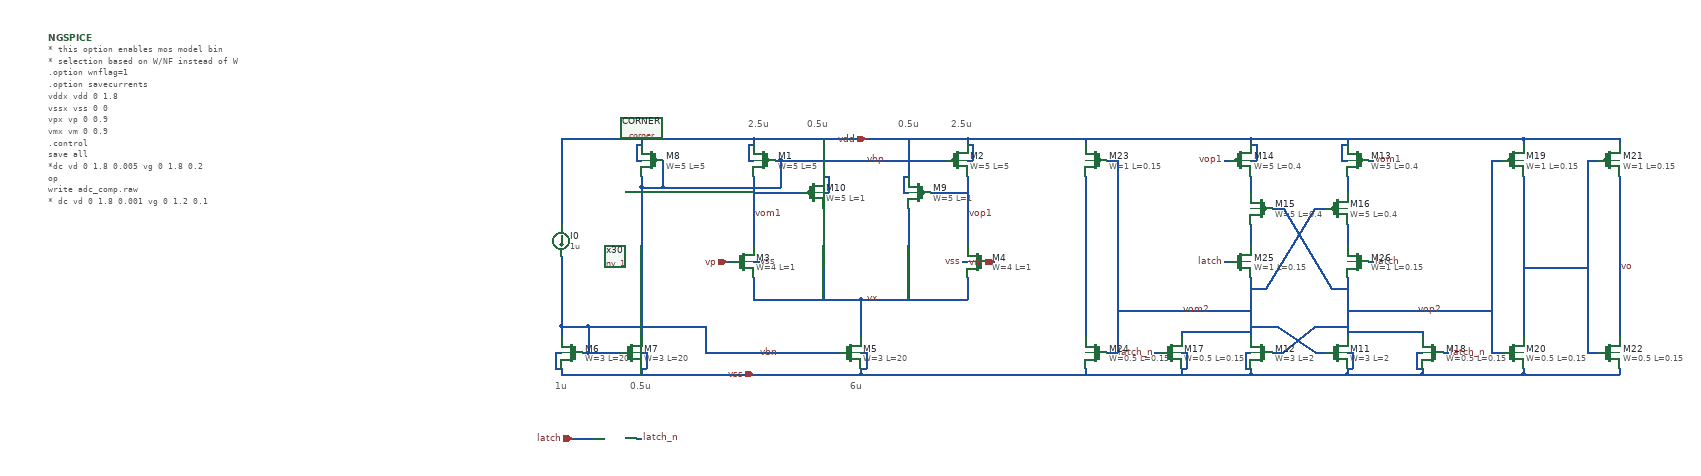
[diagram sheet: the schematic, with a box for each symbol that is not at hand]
v {xschem version=3.4.5 file_version=1.2
}
G {}
K {}
V {}
S {}
E {}
T {1u} -230 200 0 0 0.4 0.4 {}
T {0.5u} -90 200 0 0 0.4 0.4 {}
T {6u} 320 200 0 0 0.4 0.4 {}
T {2.5u} 130 -290 0 0 0.4 0.4 {}
T {2.5u} 510 -290 0 0 0.4 0.4 {}
T {0.5u} 240 -290 0 0 0.4 0.4 {}
T {0.5u} 410 -290 0 0 0.4 0.4 {}
T {0.5u} -100 -290 0 0 0.4 0.4 {}
N 140 -180 140 -50 {
lab=vom1}
N 540 -180 540 -50 {
lab=vop1}
N 130 -210 140 -210 {
lab=vdd}
N 540 -210 550 -210 {
lab=vdd}
N 330 -210 380 -210 {
lab=vbp}
N 140 10 140 50 {
lab=vx}
N 180 -210 190 -210 {
lab=vbp}
N 200 50 340 50 {
lab=vx}
N 340 50 340 110 {
lab=vx}
N -230 150 -220 150 {
lab=vss}
N -220 180 -220 190 {
lab=vss}
N -220 110 -220 120 {
lab=vbn}
N -180 150 -170 150 {
lab=vbn}
N -170 100 -170 150 {
lab=vbn}
N -220 100 -170 100 {
lab=vbn}
N -220 100 -220 110 {
lab=vbn}
N -230 150 -230 180 {
lab=vss}
N -230 180 -220 180 {
lab=vss}
N 340 150 350 150 {
lab=vss}
N 340 180 340 190 {
lab=vss}
N 340 110 340 120 {
lab=vx}
N 290 150 300 150 {
lab=vbn}
N 350 150 350 180 {
lab=vss}
N 340 180 350 180 {
lab=vss}
N -220 -30 -220 100 {
lab=vbn}
N 130 -240 130 -210 {
lab=vdd}
N 130 -240 140 -240 {
lab=vdd}
N 550 -240 550 -210 {
lab=vdd}
N 540 -240 550 -240 {
lab=vdd}
N 140 -250 140 -240 {
lab=vdd}
N 200 -250 340 -250 {
lab=vdd}
N 540 -250 540 -240 {
lab=vdd}
N 50 150 210 150 {
lab=vbn}
N 490 50 540 50 {
lab=vx}
N 540 10 540 50 {
lab=vx}
N 140 50 200 50 {
lab=vx}
N 190 -210 250 -210 {
lab=vbp}
N 450 -210 500 -210 {
lab=vbp}
N 490 -250 540 -250 {
lab=vdd}
N 140 -250 200 -250 {
lab=vdd}
N 90 -20 100 -20 {
lab=vp}
N 580 -20 590 -20 {
lab=vm}
N 530 -20 540 -20 {
lab=vss}
N 140 -20 150 -20 {
lab=vss}
N 190 -210 190 -160 {
lab=vbp}
N -220 -250 -220 -90 {
lab=vdd}
N 0 -250 140 -250 {
lab=vdd}
N -170 150 -110 150 {
lab=vbn}
N -220 190 30 190 {
lab=vss}
N -70 180 -70 190 {
lab=vss}
N -70 150 -60 150 {
lab=vss}
N -60 150 -60 170 {
lab=vss}
N -60 170 -60 180 {
lab=vss}
N -70 180 -60 180 {
lab=vss}
N -170 100 50 100 {
lab=vbn}
N 50 100 50 150 {
lab=vbn}
N 30 190 260 190 {
lab=vss}
N -220 -250 0 -250 {
lab=vdd}
N -70 -160 -70 120 {
lab=vbp}
N -70 -180 -70 -160 {
lab=vbp}
N -70 -160 -30 -160 {
lab=vbp}
N -70 -250 -70 -240 {
lab=vdd}
N -80 -210 -70 -210 {
lab=vdd}
N -80 -240 -80 -210 {
lab=vdd}
N -80 -240 -70 -240 {
lab=vdd}
N -30 -210 -30 -160 {
lab=vbp}
N 340 -250 420 -250 {
lab=vdd}
N 250 -210 330 -210 {
lab=vbp}
N 340 50 420 50 {
lab=vx}
N 420 -250 490 -250 {
lab=vdd}
N 380 -210 450 -210 {
lab=vbp}
N 420 50 490 50 {
lab=vx}
N 210 150 290 150 {
lab=vbn}
N 260 190 340 190 {
lab=vss}
N 140 -150 230 -150 {
lab=vom1}
N 470 -150 540 -150 {
lab=vop1}
N 270 -250 270 -180 {
lab=vdd}
N 430 -250 430 -180 {
lab=vdd}
N -30 -160 190 -160 {
lab=vbp}
N 270 -150 280 -150 {
lab=vdd}
N 280 -180 280 -150 {
lab=vdd}
N 270 -180 280 -180 {
lab=vdd}
N 420 -150 430 -150 {
lab=vdd}
N 420 -180 420 -150 {
lab=vdd}
N 420 -180 430 -180 {
lab=vdd}
N 270 -120 270 50 {
lab=vx}
N 430 -120 430 50 {
lab=vx}
N 1190 150 1210 150 {
lab=vom2}
N 1120 100 1190 150 {
lab=vom2}
N 1070 100 1120 100 {
lab=vom2}
N 1110 150 1130 150 {
lab=vop2}
N 1130 150 1190 100 {
lab=vop2}
N 1190 100 1250 100 {
lab=vop2}
N 1070 180 1070 190 {
lab=vss}
N 1070 190 1250 190 {
lab=vss}
N 1250 180 1250 190 {
lab=vss}
N 340 190 1070 190 {
lab=vss}
N 540 -250 1070 -250 {
lab=vdd}
N 1070 -250 1230 -250 {
lab=vdd}
N 1290 -210 1300 -210 {
lab=vom1}
N 1020 -210 1030 -210 {
lab=vop1}
N 1070 -250 1070 -240 {
lab=vdd}
N 1250 -250 1250 -240 {
lab=vdd}
N 1070 -210 1080 -210 {
lab=vdd}
N 1070 -240 1080 -240 {
lab=vdd}
N 1240 -210 1250 -210 {
lab=vdd}
N 1240 -240 1250 -240 {
lab=vdd}
N 940 110 940 120 {
lab=vom2}
N 940 110 1070 110 {
lab=vom2}
N 1390 110 1390 120 {
lab=vop2}
N 1250 110 1390 110 {
lab=vop2}
N 940 180 940 190 {
lab=vss}
N 1390 180 1390 190 {
lab=vss}
N 1250 190 1390 190 {
lab=vss}
N 1380 150 1390 150 {
lab=vss}
N 1380 150 1380 180 {
lab=vss}
N 1380 180 1390 180 {
lab=vss}
N 1250 150 1260 150 {
lab=vss}
N 1260 150 1260 180 {
lab=vss}
N 1250 180 1260 180 {
lab=vss}
N 1060 150 1070 150 {
lab=vss}
N 1060 150 1060 180 {
lab=vss}
N 1060 180 1070 180 {
lab=vss}
N 940 150 950 150 {
lab=vss}
N 950 150 950 180 {
lab=vss}
N 940 180 950 180 {
lab=vss}
N 890 150 900 150 {
lab=latch_n}
N 1430 150 1440 150 {
lab=latch_n}
N 1580 -250 1580 -240 {
lab=vdd}
N 1230 -250 1580 -250 {
lab=vdd}
N 1580 -180 1580 120 {
lab=#net1}
N 1580 180 1580 190 {
lab=vss}
N 1390 190 1580 190 {
lab=vss}
N 1520 150 1540 150 {
lab=vop2}
N 1520 -210 1520 150 {
lab=vop2}
N 1520 -210 1540 -210 {
lab=vop2}
N 1250 70 1520 70 {
lab=vop2}
N 1760 -180 1760 120 {
lab=vo}
N 1760 180 1760 190 {
lab=vss}
N 1700 150 1720 150 {
lab=#net1}
N 1700 -210 1700 150 {
lab=#net1}
N 1700 -210 1720 -210 {
lab=#net1}
N 1580 -10 1700 -10 {
lab=#net1}
N 1760 -250 1760 -240 {
lab=vdd}
N 1580 -250 1760 -250 {
lab=vdd}
N 1580 190 1760 190 {
lab=vss}
N 760 -250 760 -240 {
lab=vdd}
N 760 -180 760 120 {
lab=#net2}
N 760 180 760 190 {
lab=vss}
N 800 150 820 150 {
lab=vom2}
N 820 -210 820 150 {
lab=vom2}
N 800 -210 820 -210 {
lab=vom2}
N 820 70 1070 70 {
lab=vom2}
N 1080 -240 1080 -210 {
lab=vdd}
N 1240 -240 1240 -210 {
lab=vdd}
N 1070 -180 1070 -150 {
lab=#net3}
N 1250 -180 1250 -150 {
lab=#net4}
N 1070 -90 1070 -50 {
lab=#net5}
N 1250 -90 1250 -50 {
lab=#net6}
N 1070 10 1070 120 {
lab=vom2}
N 1250 10 1250 120 {
lab=vop2}
N 1110 -120 1130 -120 {
lab=vop2}
N 1130 -120 1220 30 {
lab=vop2}
N 1220 30 1250 30 {
lab=vop2}
N 1190 -120 1210 -120 {
lab=vom2}
N 1100 30 1190 -120 {
lab=vom2}
N 1070 30 1100 30 {
lab=vom2}
N 1290 -20 1300 -20 {
lab=latch}
N 1020 -20 1030 -20 {
lab=latch}
N -200 310 -160 310 {
lab=latch}
N -80 310 -70 310 {
lab=#net7}
C {sky130_fd_pr/nfet_01v8.sym} 120 -20 0 0 {name=M3
L=1
W=4
nf=4 
mult=4
ad="'int((nf+1)/2) * W/nf * 0.29'" 
pd="'2*int((nf+1)/2) * (W/nf + 0.29)'"
as="'int((nf+2)/2) * W/nf * 0.29'" 
ps="'2*int((nf+2)/2) * (W/nf + 0.29)'"
nrd="'0.29 / W'" nrs="'0.29 / W'"
sa=0 sb=0 sd=0
model=nfet_01v8_lvt
spiceprefix=X
}
C {sky130_fd_pr/nfet_01v8.sym} 560 -20 0 1 {name=M4
L=1
W=4
nf=4 
mult=4
ad="'int((nf+1)/2) * W/nf * 0.29'" 
pd="'2*int((nf+1)/2) * (W/nf + 0.29)'"
as="'int((nf+2)/2) * W/nf * 0.29'" 
ps="'2*int((nf+2)/2) * (W/nf + 0.29)'"
nrd="'0.29 / W'" nrs="'0.29 / W'"
sa=0 sb=0 sd=0
model=nfet_01v8_lvt
spiceprefix=X
}
C {sky130_fd_pr/pfet_01v8.sym} 520 -210 0 0 {name=M2
L=5
W=5
nf=1
mult=5
ad="'int((nf+1)/2) * W/nf * 0.29'" 
pd="'2*int((nf+1)/2) * (W/nf + 0.29)'"
as="'int((nf+2)/2) * W/nf * 0.29'" 
ps="'2*int((nf+2)/2) * (W/nf + 0.29)'"
nrd="'0.29 / W'" nrs="'0.29 / W'"
sa=0 sb=0 sd=0
model=pfet_01v8_lvt
spiceprefix=X
}
C {sky130_fd_pr/pfet_01v8.sym} 160 -210 0 1 {name=M1
L=5
W=5
nf=1
mult=5
ad="'int((nf+1)/2) * W/nf * 0.29'" 
pd="'2*int((nf+1)/2) * (W/nf + 0.29)'"
as="'int((nf+2)/2) * W/nf * 0.29'" 
ps="'2*int((nf+2)/2) * (W/nf + 0.29)'"
nrd="'0.29 / W'" nrs="'0.29 / W'"
sa=0 sb=0 sd=0
model=pfet_01v8_lvt
spiceprefix=X
}
C {sky130_fd_pr/nfet_01v8.sym} -200 150 0 1 {name=M6
L=20
W=3
nf=1
mult=2
ad="'int((nf+1)/2) * W/nf * 0.29'" 
pd="'2*int((nf+1)/2) * (W/nf + 0.29)'"
as="'int((nf+2)/2) * W/nf * 0.29'" 
ps="'2*int((nf+2)/2) * (W/nf + 0.29)'"
nrd="'0.29 / W'" nrs="'0.29 / W'"
sa=0 sb=0 sd=0
model=nfet_01v8
spiceprefix=X
}
C {sky130_fd_pr/nfet_01v8.sym} 320 150 0 0 {name=M5
L=20
W=3
nf=1
mult=12
ad="'int((nf+1)/2) * W/nf * 0.29'" 
pd="'2*int((nf+1)/2) * (W/nf + 0.29)'"
as="'int((nf+2)/2) * W/nf * 0.29'" 
ps="'2*int((nf+2)/2) * (W/nf + 0.29)'"
nrd="'0.29 / W'" nrs="'0.29 / W'"
sa=0 sb=0 sd=0
model=nfet_01v8
spiceprefix=X
}
C {iopin.sym} 140 190 1 0 {name=p1 lab=vss}
C {iopin.sym} 350 -250 3 0 {name=p2 lab=vdd}
C {devices/code_shown.sym} -1180 -440 0 0 {name=NGSPICE
only_toplevel=true
value="* this option enables mos model bin 
* selection based on W/NF instead of W
.option wnflag=1 
.option savecurrents
vddx vdd 0 1.8
vssx vss 0 0
vpx vp 0 0.9
vmx vm 0 0.9
.control
save all

*dc vd 0 1.8 0.005 vg 0 1.8 0.2
op
write adc_comp.raw
* dc vd 0 1.8 0.001 vg 0 1.2 0.1
print vbn vbp vx vdd vss vop1 vom1
print @m.xm5.msky130_fd_pr__nfet_01v8[gm]/@m.xm5.msky130_fd_pr__nfet_01v8[id]
print @m.xm5.msky130_fd_pr__nfet_01v8[gm]
print @m.xm5.msky130_fd_pr__nfet_01v8[vgs]-@m.xm5.msky130_fd_pr__nfet_01v8[vth]
print @m.xm5.msky130_fd_pr__nfet_01v8[id]
print @m.xm5.msky130_fd_pr__nfet_01v8[vth]
print @m.xm11.msky130_fd_pr__nfet_01v8[id]
print @m.xm1.msky130_fd_pr__pfet_01v8_lvt[vgs]-@m.xm1.msky130_fd_pr__pfet_01v8_lvt[vth]
print @m.xm1.msky130_fd_pr__pfet_01v8_lvt[vgs]
print @m.xm1.msky130_fd_pr__pfet_01v8_lvt[gm]/@m.xm1.msky130_fd_pr__pfet_01v8_lvt[id]
print @m.xm1.msky130_fd_pr__pfet_01v8_lvt[vth]
print @m.xm1.msky130_fd_pr__pfet_01v8_lvt[id]
print @m.xm3.msky130_fd_pr__nfet_01v8_lvt[vgs]-@m.xm3.msky130_fd_pr__nfet_01v8_lvt[vth]
print @m.xm3.msky130_fd_pr__nfet_01v8_lvt[vgs]
print @m.xm3.msky130_fd_pr__nfet_01v8_lvt[gm]/@m.xm3.msky130_fd_pr__nfet_01v8_lvt[id]
print @m.xm3.msky130_fd_pr__nfet_01v8_lvt[vth]
print @m.xm3.msky130_fd_pr__nfet_01v8_lvt[id]
print @m.xm10.msky130_fd_pr__pfet_01v8_lvt[id]
set appendwrite
op
.endc
"}
C {ipin.sym} 90 -20 0 0 {name=p3 lab=vp}
C {ipin.sym} 590 -20 2 0 {name=p4 lab=vm}
C {lab_wire.sym} 150 -20 2 0 {name=p5 sig_type=std_logic lab=vss}
C {lab_wire.sym} 530 -20 0 0 {name=p6 sig_type=std_logic lab=vss}
C {sky130_fd_pr/corner.sym} -540 -420 0 0 {name=CORNER only_toplevel=true corner=tt}
C {isource.sym} -220 -60 0 0 {name=I0 value=1u}
C {lab_wire.sym} 150 150 2 0 {name=p7 sig_type=std_logic lab=vbn}
C {lab_wire.sym} 350 -210 2 0 {name=p8 sig_type=std_logic lab=vbp}
C {lab_wire.sym} 350 50 2 0 {name=p9 sig_type=std_logic lab=vx}
C {sky130_fd_pr/nfet_01v8.sym} -90 150 0 0 {name=M7
L=20
W=3
nf=1
mult=1
ad="'int((nf+1)/2) * W/nf * 0.29'" 
pd="'2*int((nf+1)/2) * (W/nf + 0.29)'"
as="'int((nf+2)/2) * W/nf * 0.29'" 
ps="'2*int((nf+2)/2) * (W/nf + 0.29)'"
nrd="'0.29 / W'" nrs="'0.29 / W'"
sa=0 sb=0 sd=0
model=nfet_01v8
spiceprefix=X
}
C {sky130_fd_pr/pfet_01v8.sym} -50 -210 0 1 {name=M8
L=5
W=5
nf=1
mult=1
ad="'int((nf+1)/2) * W/nf * 0.29'" 
pd="'2*int((nf+1)/2) * (W/nf + 0.29)'"
as="'int((nf+2)/2) * W/nf * 0.29'" 
ps="'2*int((nf+2)/2) * (W/nf + 0.29)'"
nrd="'0.29 / W'" nrs="'0.29 / W'"
sa=0 sb=0 sd=0
model=pfet_01v8_lvt
spiceprefix=X
}
C {lab_wire.sym} 140 -110 2 0 {name=p10 sig_type=std_logic lab=vom1}
C {lab_wire.sym} 540 -110 2 0 {name=p11 sig_type=std_logic lab=vop1
}
C {sky130_fd_pr/pfet_01v8.sym} 450 -150 0 1 {name=M9
L=1
W=5
nf=1
mult=2
ad="'int((nf+1)/2) * W/nf * 0.29'" 
pd="'2*int((nf+1)/2) * (W/nf + 0.29)'"
as="'int((nf+2)/2) * W/nf * 0.29'" 
ps="'2*int((nf+2)/2) * (W/nf + 0.29)'"
nrd="'0.29 / W'" nrs="'0.29 / W'"
sa=0 sb=0 sd=0
model=pfet_01v8_lvt
spiceprefix=X
}
C {sky130_fd_pr/pfet_01v8.sym} 250 -150 0 0 {name=M10
L=1
W=5
nf=1
mult=2
ad="'int((nf+1)/2) * W/nf * 0.29'" 
pd="'2*int((nf+1)/2) * (W/nf + 0.29)'"
as="'int((nf+2)/2) * W/nf * 0.29'" 
ps="'2*int((nf+2)/2) * (W/nf + 0.29)'"
nrd="'0.29 / W'" nrs="'0.29 / W'"
sa=0 sb=0 sd=0
model=pfet_01v8_lvt
spiceprefix=X
}
C {sky130_fd_pr/nfet_01v8.sym} 1230 150 0 0 {name=M11
L=2
W=3
nf=1
mult=1
ad="'int((nf+1)/2) * W/nf * 0.29'" 
pd="'2*int((nf+1)/2) * (W/nf + 0.29)'"
as="'int((nf+2)/2) * W/nf * 0.29'" 
ps="'2*int((nf+2)/2) * (W/nf + 0.29)'"
nrd="'0.29 / W'" nrs="'0.29 / W'"
sa=0 sb=0 sd=0
model=nfet_01v8
spiceprefix=X
}
C {sky130_fd_pr/nfet_01v8.sym} 1090 150 0 1 {name=M12
L=2
W=3
nf=1
mult=1
ad="'int((nf+1)/2) * W/nf * 0.29'" 
pd="'2*int((nf+1)/2) * (W/nf + 0.29)'"
as="'int((nf+2)/2) * W/nf * 0.29'" 
ps="'2*int((nf+2)/2) * (W/nf + 0.29)'"
nrd="'0.29 / W'" nrs="'0.29 / W'"
sa=0 sb=0 sd=0
model=nfet_01v8
spiceprefix=X
}
C {sky130_fd_pr/pfet_01v8.sym} 1270 -210 0 1 {name=M13
L=0.4
W=5
nf=1
mult=1
ad="'int((nf+1)/2) * W/nf * 0.29'" 
pd="'2*int((nf+1)/2) * (W/nf + 0.29)'"
as="'int((nf+2)/2) * W/nf * 0.29'" 
ps="'2*int((nf+2)/2) * (W/nf + 0.29)'"
nrd="'0.29 / W'" nrs="'0.29 / W'"
sa=0 sb=0 sd=0
model=pfet_01v8_lvt
spiceprefix=X
}
C {sky130_fd_pr/pfet_01v8.sym} 1050 -210 0 0 {name=M14
L=0.4
W=5
nf=1
mult=1
ad="'int((nf+1)/2) * W/nf * 0.29'" 
pd="'2*int((nf+1)/2) * (W/nf + 0.29)'"
as="'int((nf+2)/2) * W/nf * 0.29'" 
ps="'2*int((nf+2)/2) * (W/nf + 0.29)'"
nrd="'0.29 / W'" nrs="'0.29 / W'"
sa=0 sb=0 sd=0
model=pfet_01v8_lvt
spiceprefix=X
}
C {lab_wire.sym} 1020 -210 0 0 {name=p12 sig_type=std_logic lab=vop1
}
C {lab_wire.sym} 1300 -210 0 1 {name=p13 sig_type=std_logic lab=vom1
}
C {sky130_fd_pr/nfet_01v8.sym} 920 150 0 0 {name=M17
L=0.15
W=0.5
nf=1
mult=1
ad="'int((nf+1)/2) * W/nf * 0.29'" 
pd="'2*int((nf+1)/2) * (W/nf + 0.29)'"
as="'int((nf+2)/2) * W/nf * 0.29'" 
ps="'2*int((nf+2)/2) * (W/nf + 0.29)'"
nrd="'0.29 / W'" nrs="'0.29 / W'"
sa=0 sb=0 sd=0
model=nfet_01v8
spiceprefix=X
}
C {sky130_fd_pr/nfet_01v8.sym} 1410 150 0 1 {name=M18
L=0.15
W=0.5
nf=1
mult=1
ad="'int((nf+1)/2) * W/nf * 0.29'" 
pd="'2*int((nf+1)/2) * (W/nf + 0.29)'"
as="'int((nf+2)/2) * W/nf * 0.29'" 
ps="'2*int((nf+2)/2) * (W/nf + 0.29)'"
nrd="'0.29 / W'" nrs="'0.29 / W'"
sa=0 sb=0 sd=0
model=nfet_01v8
spiceprefix=X
}
C {lab_wire.sym} 890 150 0 0 {name=p16 sig_type=std_logic lab=latch_n

}
C {lab_wire.sym} 1440 150 2 0 {name=p17 sig_type=std_logic lab=latch_n

}
C {sky130_fd_pr/pfet_01v8.sym} 1560 -210 0 0 {name=M19
L=0.15
W=1
nf=1
mult=1
ad="'int((nf+1)/2) * W/nf * 0.29'" 
pd="'2*int((nf+1)/2) * (W/nf + 0.29)'"
as="'int((nf+2)/2) * W/nf * 0.29'" 
ps="'2*int((nf+2)/2) * (W/nf + 0.29)'"
nrd="'0.29 / W'" nrs="'0.29 / W'"
sa=0 sb=0 sd=0
model=pfet_01v8
spiceprefix=X
}
C {sky130_fd_pr/nfet_01v8.sym} 1560 150 0 0 {name=M20
L=0.15
W=0.5
nf=1
mult=1
ad="'int((nf+1)/2) * W/nf * 0.29'" 
pd="'2*int((nf+1)/2) * (W/nf + 0.29)'"
as="'int((nf+2)/2) * W/nf * 0.29'" 
ps="'2*int((nf+2)/2) * (W/nf + 0.29)'"
nrd="'0.29 / W'" nrs="'0.29 / W'"
sa=0 sb=0 sd=0
model=nfet_01v8
spiceprefix=X
}
C {sky130_fd_pr/pfet_01v8.sym} 1740 -210 0 0 {name=M21
L=0.15
W=1
nf=1
mult=2
ad="'int((nf+1)/2) * W/nf * 0.29'" 
pd="'2*int((nf+1)/2) * (W/nf + 0.29)'"
as="'int((nf+2)/2) * W/nf * 0.29'" 
ps="'2*int((nf+2)/2) * (W/nf + 0.29)'"
nrd="'0.29 / W'" nrs="'0.29 / W'"
sa=0 sb=0 sd=0
model=pfet_01v8
spiceprefix=X
}
C {sky130_fd_pr/nfet_01v8.sym} 1740 150 0 0 {name=M22
L=0.15
W=0.5
nf=1
mult=2
ad="'int((nf+1)/2) * W/nf * 0.29'" 
pd="'2*int((nf+1)/2) * (W/nf + 0.29)'"
as="'int((nf+2)/2) * W/nf * 0.29'" 
ps="'2*int((nf+2)/2) * (W/nf + 0.29)'"
nrd="'0.29 / W'" nrs="'0.29 / W'"
sa=0 sb=0 sd=0
model=nfet_01v8
spiceprefix=X
}
C {lab_wire.sym} 1380 70 2 0 {name=p18 sig_type=std_logic lab=vop2
}
C {sky130_fd_pr/pfet_01v8.sym} 780 -210 0 1 {name=M23
L=0.15
W=1
nf=1
mult=1
ad="'int((nf+1)/2) * W/nf * 0.29'" 
pd="'2*int((nf+1)/2) * (W/nf + 0.29)'"
as="'int((nf+2)/2) * W/nf * 0.29'" 
ps="'2*int((nf+2)/2) * (W/nf + 0.29)'"
nrd="'0.29 / W'" nrs="'0.29 / W'"
sa=0 sb=0 sd=0
model=pfet_01v8
spiceprefix=X
}
C {sky130_fd_pr/nfet_01v8.sym} 780 150 0 1 {name=M24
L=0.15
W=0.5
nf=1
mult=1
ad="'int((nf+1)/2) * W/nf * 0.29'" 
pd="'2*int((nf+1)/2) * (W/nf + 0.29)'"
as="'int((nf+2)/2) * W/nf * 0.29'" 
ps="'2*int((nf+2)/2) * (W/nf + 0.29)'"
nrd="'0.29 / W'" nrs="'0.29 / W'"
sa=0 sb=0 sd=0
model=nfet_01v8
spiceprefix=X
}
C {lab_wire.sym} 940 70 2 0 {name=p19 sig_type=std_logic lab=vom2
}
C {lab_wire.sym} 1760 -10 2 0 {name=p20 sig_type=std_logic lab=vo
}
C {ipin.sym} -200 310 0 0 {name=p21 lab=latch}
C {sky130_fd_pr/pfet_01v8.sym} 1090 -120 0 1 {name=M15
L=0.4
W=5
nf=1
mult=1
ad="'int((nf+1)/2) * W/nf * 0.29'" 
pd="'2*int((nf+1)/2) * (W/nf + 0.29)'"
as="'int((nf+2)/2) * W/nf * 0.29'" 
ps="'2*int((nf+2)/2) * (W/nf + 0.29)'"
nrd="'0.29 / W'" nrs="'0.29 / W'"
sa=0 sb=0 sd=0
model=pfet_01v8_lvt
spiceprefix=X
}
C {sky130_fd_pr/pfet_01v8.sym} 1230 -120 0 0 {name=M16
L=0.4
W=5
nf=1
mult=1
ad="'int((nf+1)/2) * W/nf * 0.29'" 
pd="'2*int((nf+1)/2) * (W/nf + 0.29)'"
as="'int((nf+2)/2) * W/nf * 0.29'" 
ps="'2*int((nf+2)/2) * (W/nf + 0.29)'"
nrd="'0.29 / W'" nrs="'0.29 / W'"
sa=0 sb=0 sd=0
model=pfet_01v8_lvt
spiceprefix=X
}
C {sky130_fd_pr/nfet_01v8.sym} 1050 -20 0 0 {name=M25
L=0.15
W=1
nf=1
mult=1
ad="'int((nf+1)/2) * W/nf * 0.29'" 
pd="'2*int((nf+1)/2) * (W/nf + 0.29)'"
as="'int((nf+2)/2) * W/nf * 0.29'" 
ps="'2*int((nf+2)/2) * (W/nf + 0.29)'"
nrd="'0.29 / W'" nrs="'0.29 / W'"
sa=0 sb=0 sd=0
model=nfet_01v8_lvt
spiceprefix=X
}
C {sky130_fd_pr/nfet_01v8.sym} 1270 -20 0 1 {name=M26
L=0.15
W=1
nf=1
mult=1
ad="'int((nf+1)/2) * W/nf * 0.29'" 
pd="'2*int((nf+1)/2) * (W/nf + 0.29)'"
as="'int((nf+2)/2) * W/nf * 0.29'" 
ps="'2*int((nf+2)/2) * (W/nf + 0.29)'"
nrd="'0.29 / W'" nrs="'0.29 / W'"
sa=0 sb=0 sd=0
model=nfet_01v8_lvt
spiceprefix=X
}
C {lab_wire.sym} 1300 -20 2 0 {name=p14 sig_type=std_logic lab=latch

}
C {lab_wire.sym} 1020 -20 0 0 {name=p15 sig_type=std_logic lab=latch

}
C {sky130_stdcells/inv_1.sym} -120 310 0 0 {name=x30 VGND=vss VNB=vss VPB=vdd VPWR=vdd prefix=sky130_fd_sc_hd__ }
C {lab_wire.sym} -70 310 2 0 {name=p22 sig_type=std_logic lab=latch_n

}
